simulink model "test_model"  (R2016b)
settings: Solver=VariableStepAuto  StartTime=0.0  StopTime=runtime  RelTol=1e-3
InitFcn:
  | clear mex
  | delete test_model_sfun.mexw64
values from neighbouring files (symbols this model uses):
  g = 9.81    [modelParameters.m]
  height_controlled_o = (((Rm*If +      + (((omega0_o * 2 * Rm * Kv * Kq       * Kd + 1)^2) - 1)/(4* Rm*Kv^2*Kq      *Kd))/Vb)*(Pmax- Pmin)+Pmin)    [modelParameters.m]
  If = 0.511    [modelParameters.m]
  Jreq = 4.2012e-05    [modelParameters.m]
  Jxx = 0.0130    (= 0.013)    [modelParameters.m]
  Jyy = 0.0140    (= 0.014)    [modelParameters.m]
  Jzz = 0.0285    [modelParameters.m]
  Kd = 1.0317e-7    (= 1.0317e-07)    [modelParameters.m]
  Kq = 96.3422    [modelParameters.m]
  Kt = 8.6519e-6    (= 8.6519e-06)    [modelParameters.m]
  Kv = 96.3422    [modelParameters.m]
  m = 1.244    [modelParameters.m]
  omega0_o = (-1 + sqrt(1 - 4*Rm*Kv*Kq*Kd*( Kv*Rm*If - Kv*Vb_eff_0))) / (2*Rm*Kv*Kq*Kd)    [modelParameters.m]
  omega1_o = (-1 + sqrt(1 - 4*Rm*Kv*Kq*Kd*( Kv*Rm*If - Kv*Vb_eff_1))) / (2*Rm*Kv*Kq*Kd)    [modelParameters.m]
  omega2_o = (-1 + sqrt(1 - 4*Rm*Kv*Kq*Kd*( Kv*Rm*If - Kv*Vb_eff_2))) / (2*Rm*Kv*Kq*Kd)    [modelParameters.m]
  omega3_o = (-1 + sqrt(1 - 4*Rm*Kv*Kq*Kd*( Kv*Rm*If - Kv*Vb_eff_3))) / (2*Rm*Kv*Kq*Kd)    [modelParameters.m]
  pitch_o = pitch_value(1)    [modelParameters.m]
  pitchrate_o = pitchrate_value(1)    [modelParameters.m]
  Pmax = 2e5    (= 200000)    [modelParameters.m]
  Pmin = 1e5    (= 100000)    [modelParameters.m]
  rhx = 0.16    [modelParameters.m]
  rhy = 0.16    [modelParameters.m]
  rhz = 0.03    [modelParameters.m]
  Rm = 0.2308    [modelParameters.m]
  roll_o = roll_value(1)    [modelParameters.m]
  rollrate_o = rollrate_value(1)    [modelParameters.m]
  Tc = 0.04    [modelParameters.m]
  Tq = 0.005    [modelParameters.m]
  Vb = 11.1    [modelParameters.m]
  x_controlled_o = 0    [modelParameters.m]
  x_o = x_position(1)    [modelParameters.m]
  x_vel_o = (x_position(2) - x_position(1)) / (time(2) - time(1))    [modelParameters.m]
  y_controlled_o = 0    [modelParameters.m]
  y_o = y_position(1)    [modelParameters.m]
  y_vel_o = (y_position(2) - y_position(1)) / (time(2) - time(1))    [modelParameters.m]
  yaw_controlled_o = 0    [modelParameters.m]
  yaw_o = yaw_value(1)    [modelParameters.m]
  yawrate_o = yawrate_value(1)    [modelParameters.m]
  z_o = z_position(1)    [modelParameters.m]
  z_vel_o = (z_position(2) - z_position(1)) / (time(2) - time(1))    [modelParameters.m]
undefined symbols (not defined in the file or in its folder): DiscIntNeverNeededParam
libraries: simulink x21, vrlib x2
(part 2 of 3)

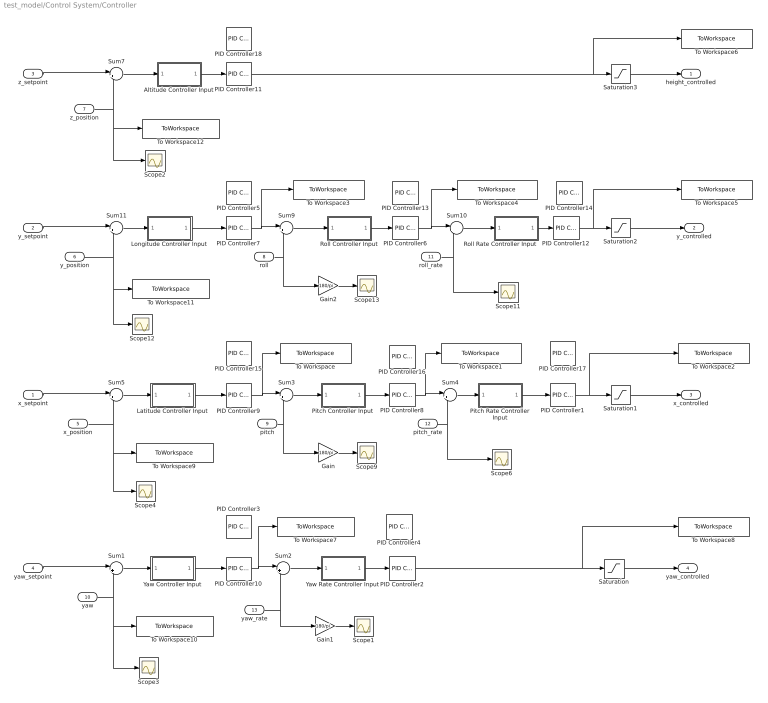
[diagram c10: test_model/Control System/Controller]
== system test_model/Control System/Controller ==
  x_setpoint : Inport
  y_setpoint : Inport  Port=2
  z_setpoint : Inport  Port=3
  yaw_setpoint : Inport  Port=4
  x_position : Inport  Port=5
  y_position : Inport  Port=6
  z_position : Inport  Port=7
  roll : Inport  Port=8
  pitch : Inport  Port=9
  yaw : Inport  Port=10
  roll_rate : Inport  Port=11
  pitch_rate : Inport  Port=12
  yaw_rate : Inport  Port=13
  Altitude Controller Input : Subsystem  Variant=on
  Gain : Gain  Gain=180/pi
  Gain1 : Gain  Gain=180/pi
  Gain2 : Gain  Gain=180/pi
  Latitude Controller Input : Subsystem  Variant=on
  Longitude Controller Input : Subsystem  Variant=on
  PID Controller1 : simulink/Continuous/PID Controller  Controller=PD  TimeDomain=Discrete-time  SampleTime=Tq  IntegratorMethod=Forward Euler  FilterMethod=Forward Euler  Form=Parallel  UseFilter=off  ControllerParametersSource=internal  P=4600  I=1575.82088970639  D=550  N=244.660686071579  InitialConditionSource=internal  InitialConditionForIntegrator=0  InitialConditionForFilter=0  ExternalReset=none  LimitOutput=off  UpperSaturationLimit=inf  LowerSaturationLimit=-inf  LinearizeAsGain=on  AntiWindupMode=none  Kb=1  TrackingMode=off  Kt=1  PParamMin=[]  PParamMax=[]  IParamMin=[]  IParamMax=[]  DParamMin=[]  DParamMax=[]  NParamMin=[]  NParamMax=[]  KbParamMin=[]  KbParamMax=[]  KtParamMin=[]  KtParamMax=[]  POutMin=[]  POutMax=[]  IOutMin=[]  IOutMax=[]  DOutMin=[]  DOutMax=[]  NOutMin=[]  NOutMax=[]  KbOutMin=[]  KbOutMax=[]  KtOutMin=[]  KtOutMax=[]  IntegratorOutMin=[]  IntegratorOutMax=[]  FilterOutMin=[]  FilterOutMax=[]  SumOutMin=[]  SumOutMax=[]  SumI1OutMin=[]  SumI1OutMax=[]  SumI2OutMin=[]  SumI2OutMax=[]  SumI3OutMin=[]  SumI3OutMax=[]  SumDOutMin=[]  SumDOutMax=[]  SaturationOutMin=[]  SaturationOutMax=[]  IntegratorContinuousStateAttributes=''  IntegratorStateMustResolveToSignalObject=off  IntegratorRTWStateStorageClass=Auto  FilterContinuousStateAttributes=''  FilterStateMustResolveToSignalObject=off  FilterRTWStateStorageClass=Auto  DifferentiatorICPrevScaledInput=0  DifferentiatorOutMin=[]  DifferentiatorOutMax=[]
  PID Controller10 : simulink/Continuous/PID Controller  Controller=PD  TimeDomain=Discrete-time  SampleTime=Tc  IntegratorMethod=Forward Euler  FilterMethod=Forward Euler  Form=Parallel  UseFilter=off  ControllerParametersSource=internal  P=2.6  I=2.36803176515497  D=0  N=3.83298618768959  InitialConditionSource=internal  InitialConditionForIntegrator=0  InitialConditionForFilter=0  ExternalReset=none  LimitOutput=off  UpperSaturationLimit=inf  LowerSaturationLimit=-inf  LinearizeAsGain=on  AntiWindupMode=none  Kb=1  TrackingMode=off  Kt=1  PParamMin=[]  PParamMax=[]  IParamMin=[]  IParamMax=[]  DParamMin=[]  DParamMax=[]  NParamMin=[]  NParamMax=[]  KbParamMin=[]  KbParamMax=[]  KtParamMin=[]  KtParamMax=[]  POutMin=[]  POutMax=[]  IOutMin=[]  IOutMax=[]  DOutMin=[]  DOutMax=[]  NOutMin=[]  NOutMax=[]  KbOutMin=[]  KbOutMax=[]  KtOutMin=[]  KtOutMax=[]  IntegratorOutMin=[]  IntegratorOutMax=[]  FilterOutMin=[]  FilterOutMax=[]  SumOutMin=[]  SumOutMax=[]  SumI1OutMin=[]  SumI1OutMax=[]  SumI2OutMin=[]  SumI2OutMax=[]  SumI3OutMin=[]  SumI3OutMax=[]  SumDOutMin=[]  SumDOutMax=[]  SaturationOutMin=[]  SaturationOutMax=[]  IntegratorContinuousStateAttributes=''  IntegratorStateMustResolveToSignalObject=off  IntegratorRTWStateStorageClass=Auto  FilterContinuousStateAttributes=''  FilterStateMustResolveToSignalObject=off  FilterRTWStateStorageClass=Auto  DifferentiatorICPrevScaledInput=0  DifferentiatorOutMin=[]  DifferentiatorOutMax=[]
  PID Controller11 : simulink/Continuous/PID Controller  Controller=PID  TimeDomain=Discrete-time  SampleTime=Tc  IntegratorMethod=Forward Euler  FilterMethod=Forward Euler  Form=Parallel  UseFilter=off  ControllerParametersSource=internal  P=9804  I=817  D=7353  N=5.79502261645411  InitialConditionSource=internal  InitialConditionForIntegrator=0  InitialConditionForFilter=0  ExternalReset=none  LimitOutput=off  UpperSaturationLimit=inf  LowerSaturationLimit=-inf  LinearizeAsGain=on  AntiWindupMode=none  Kb=1  TrackingMode=off  Kt=1  PParamMin=[]  PParamMax=[]  IParamMin=[]  IParamMax=[]  DParamMin=[]  DParamMax=[]  NParamMin=[]  NParamMax=[]  KbParamMin=[]  KbParamMax=[]  KtParamMin=[]  KtParamMax=[]  POutMin=[]  POutMax=[]  IOutMin=[]  IOutMax=[]  DOutMin=[]  DOutMax=[]  NOutMin=[]  NOutMax=[]  KbOutMin=[]  KbOutMax=[]  KtOutMin=[]  KtOutMax=[]  IntegratorOutMin=[]  IntegratorOutMax=[]  FilterOutMin=[]  FilterOutMax=[]  SumOutMin=[]  SumOutMax=[]  SumI1OutMin=[]  SumI1OutMax=[]  SumI2OutMin=[]  SumI2OutMax=[]  SumI3OutMin=[]  SumI3OutMax=[]  SumDOutMin=[]  SumDOutMax=[]  SaturationOutMin=[]  SaturationOutMax=[]  IntegratorContinuousStateAttributes=''  IntegratorStateMustResolveToSignalObject=off  IntegratorRTWStateStorageClass=Auto  FilterContinuousStateAttributes=''  FilterStateMustResolveToSignalObject=off  FilterRTWStateStorageClass=Auto  DifferentiatorICPrevScaledInput=0  DifferentiatorOutMin=[]  DifferentiatorOutMax=[]
  PID Controller12 : simulink/Continuous/PID Controller  Controller=PD  TimeDomain=Discrete-time  SampleTime=Tq  IntegratorMethod=Forward Euler  FilterMethod=Forward Euler  Form=Parallel  UseFilter=off  ControllerParametersSource=internal  P=4600  I=1575.82088970639  D=550  N=244.660686071579  InitialConditionSource=internal  InitialConditionForIntegrator=0  InitialConditionForFilter=0  ExternalReset=none  LimitOutput=off  UpperSaturationLimit=inf  LowerSaturationLimit=-inf  LinearizeAsGain=on  AntiWindupMode=none  Kb=1  TrackingMode=off  Kt=1  PParamMin=[]  PParamMax=[]  IParamMin=[]  IParamMax=[]  DParamMin=[]  DParamMax=[]  NParamMin=[]  NParamMax=[]  KbParamMin=[]  KbParamMax=[]  KtParamMin=[]  KtParamMax=[]  POutMin=[]  POutMax=[]  IOutMin=[]  IOutMax=[]  DOutMin=[]  DOutMax=[]  NOutMin=[]  NOutMax=[]  KbOutMin=[]  KbOutMax=[]  KtOutMin=[]  KtOutMax=[]  IntegratorOutMin=[]  IntegratorOutMax=[]  FilterOutMin=[]  FilterOutMax=[]  SumOutMin=[]  SumOutMax=[]  SumI1OutMin=[]  SumI1OutMax=[]  SumI2OutMin=[]  SumI2OutMax=[]  SumI3OutMin=[]  SumI3OutMax=[]  SumDOutMin=[]  SumDOutMax=[]  SaturationOutMin=[]  SaturationOutMax=[]  IntegratorContinuousStateAttributes=''  IntegratorStateMustResolveToSignalObject=off  IntegratorRTWStateStorageClass=Auto  FilterContinuousStateAttributes=''  FilterStateMustResolveToSignalObject=off  FilterRTWStateStorageClass=Auto  DifferentiatorICPrevScaledInput=0  DifferentiatorOutMin=[]  DifferentiatorOutMax=[]
  PID Controller13 : simulink/Continuous/PID Controller  Controller=P  TimeDomain=Discrete-time  SampleTime=Tc  IntegratorMethod=Forward Euler  FilterMethod=Forward Euler  Form=Parallel  UseFilter=off  ControllerParametersSource=internal  P=1  I=35.1207902652377  D=0.2  N=40.0107970227961  InitialConditionSource=internal  InitialConditionForIntegrator=0  InitialConditionForFilter=0  ExternalReset=none  LimitOutput=off  UpperSaturationLimit=inf  LowerSaturationLimit=-inf  LinearizeAsGain=on  AntiWindupMode=none  Kb=1  TrackingMode=off  Kt=1  PParamMin=[]  PParamMax=[]  IParamMin=[]  IParamMax=[]  DParamMin=[]  DParamMax=[]  NParamMin=[]  NParamMax=[]  KbParamMin=[]  KbParamMax=[]  KtParamMin=[]  KtParamMax=[]  POutMin=[]  POutMax=[]  IOutMin=[]  IOutMax=[]  DOutMin=[]  DOutMax=[]  NOutMin=[]  NOutMax=[]  KbOutMin=[]  KbOutMax=[]  KtOutMin=[]  KtOutMax=[]  IntegratorOutMin=[]  IntegratorOutMax=[]  FilterOutMin=[]  FilterOutMax=[]  SumOutMin=[]  SumOutMax=[]  SumI1OutMin=[]  SumI1OutMax=[]  SumI2OutMin=[]  SumI2OutMax=[]  SumI3OutMin=[]  SumI3OutMax=[]  SumDOutMin=[]  SumDOutMax=[]  SaturationOutMin=[]  SaturationOutMax=[]  IntegratorContinuousStateAttributes=''  IntegratorStateMustResolveToSignalObject=off  IntegratorRTWStateStorageClass=Auto  FilterContinuousStateAttributes=''  FilterStateMustResolveToSignalObject=off  FilterRTWStateStorageClass=Auto  DifferentiatorICPrevScaledInput=0  DifferentiatorOutMin=[]  DifferentiatorOutMax=[]
  PID Controller14 : simulink/Continuous/PID Controller  Controller=P  TimeDomain=Discrete-time  SampleTime=Tq  IntegratorMethod=Forward Euler  FilterMethod=Forward Euler  Form=Parallel  UseFilter=off  ControllerParametersSource=internal  P=1835.12180866282  I=1575.82088970639  D=550  N=244.660686071579  InitialConditionSource=internal  InitialConditionForIntegrator=0  InitialConditionForFilter=0  ExternalReset=none  LimitOutput=off  UpperSaturationLimit=inf  LowerSaturationLimit=-inf  LinearizeAsGain=on  AntiWindupMode=none  Kb=1  TrackingMode=off  Kt=1  PParamMin=[]  PParamMax=[]  IParamMin=[]  IParamMax=[]  DParamMin=[]  DParamMax=[]  NParamMin=[]  NParamMax=[]  KbParamMin=[]  KbParamMax=[]  KtParamMin=[]  KtParamMax=[]  POutMin=[]  POutMax=[]  IOutMin=[]  IOutMax=[]  DOutMin=[]  DOutMax=[]  NOutMin=[]  NOutMax=[]  KbOutMin=[]  KbOutMax=[]  KtOutMin=[]  KtOutMax=[]  IntegratorOutMin=[]  IntegratorOutMax=[]  FilterOutMin=[]  FilterOutMax=[]  SumOutMin=[]  SumOutMax=[]  SumI1OutMin=[]  SumI1OutMax=[]  SumI2OutMin=[]  SumI2OutMax=[]  SumI3OutMin=[]  SumI3OutMax=[]  SumDOutMin=[]  SumDOutMax=[]  SaturationOutMin=[]  SaturationOutMax=[]  IntegratorContinuousStateAttributes=''  IntegratorStateMustResolveToSignalObject=off  IntegratorRTWStateStorageClass=Auto  FilterContinuousStateAttributes=''  FilterStateMustResolveToSignalObject=off  FilterRTWStateStorageClass=Auto  DifferentiatorICPrevScaledInput=0  DifferentiatorOutMin=[]  DifferentiatorOutMax=[]
  PID Controller15 : simulink/Continuous/PID Controller  Controller=PD  TimeDomain=Discrete-time  SampleTime=Tc  IntegratorMethod=Forward Euler  FilterMethod=Forward Euler  Form=Parallel  UseFilter=on  ControllerParametersSource=internal  P=-0.00239291827793903  I=0.005  D=-0.101936697537801  N=33.9318377685715  InitialConditionSource=internal  InitialConditionForIntegrator=0  InitialConditionForFilter=0  ExternalReset=none  LimitOutput=off  UpperSaturationLimit=inf  LowerSaturationLimit=-inf  LinearizeAsGain=on  AntiWindupMode=none  Kb=1  TrackingMode=off  Kt=1  PParamMin=[]  PParamMax=[]  IParamMin=[]  IParamMax=[]  DParamMin=[]  DParamMax=[]  NParamMin=[]  NParamMax=[]  KbParamMin=[]  KbParamMax=[]  KtParamMin=[]  KtParamMax=[]  POutMin=[]  POutMax=[]  IOutMin=[]  IOutMax=[]  DOutMin=[]  DOutMax=[]  NOutMin=[]  NOutMax=[]  KbOutMin=[]  KbOutMax=[]  KtOutMin=[]  KtOutMax=[]  IntegratorOutMin=[]  IntegratorOutMax=[]  FilterOutMin=[]  FilterOutMax=[]  SumOutMin=[]  SumOutMax=[]  SumI1OutMin=[]  SumI1OutMax=[]  SumI2OutMin=[]  SumI2OutMax=[]  SumI3OutMin=[]  SumI3OutMax=[]  SumDOutMin=[]  SumDOutMax=[]  SaturationOutMin=[]  SaturationOutMax=[]  IntegratorContinuousStateAttributes=''  IntegratorStateMustResolveToSignalObject=off  IntegratorRTWStateStorageClass=Auto  FilterContinuousStateAttributes=''  FilterStateMustResolveToSignalObject=off  FilterRTWStateStorageClass=Auto  DifferentiatorICPrevScaledInput=0  DifferentiatorOutMin=[]  DifferentiatorOutMax=[]
  PID Controller16 : simulink/Continuous/PID Controller  Controller=P  TimeDomain=Discrete-time  SampleTime=Tc  IntegratorMethod=Forward Euler  FilterMethod=Forward Euler  Form=Parallel  UseFilter=off  ControllerParametersSource=internal  P=1  I=35.1207902652377  D=0.2  N=40.0107970227961  InitialConditionSource=internal  InitialConditionForIntegrator=0  InitialConditionForFilter=0  ExternalReset=none  LimitOutput=off  UpperSaturationLimit=inf  LowerSaturationLimit=-inf  LinearizeAsGain=on  AntiWindupMode=none  Kb=1  TrackingMode=off  Kt=1  PParamMin=[]  PParamMax=[]  IParamMin=[]  IParamMax=[]  DParamMin=[]  DParamMax=[]  NParamMin=[]  NParamMax=[]  KbParamMin=[]  KbParamMax=[]  KtParamMin=[]  KtParamMax=[]  POutMin=[]  POutMax=[]  IOutMin=[]  IOutMax=[]  DOutMin=[]  DOutMax=[]  NOutMin=[]  NOutMax=[]  KbOutMin=[]  KbOutMax=[]  KtOutMin=[]  KtOutMax=[]  IntegratorOutMin=[]  IntegratorOutMax=[]  FilterOutMin=[]  FilterOutMax=[]  SumOutMin=[]  SumOutMax=[]  SumI1OutMin=[]  SumI1OutMax=[]  SumI2OutMin=[]  SumI2OutMax=[]  SumI3OutMin=[]  SumI3OutMax=[]  SumDOutMin=[]  SumDOutMax=[]  SaturationOutMin=[]  SaturationOutMax=[]  IntegratorContinuousStateAttributes=''  IntegratorStateMustResolveToSignalObject=off  IntegratorRTWStateStorageClass=Auto  FilterContinuousStateAttributes=''  FilterStateMustResolveToSignalObject=off  FilterRTWStateStorageClass=Auto  DifferentiatorICPrevScaledInput=0  DifferentiatorOutMin=[]  DifferentiatorOutMax=[]
  PID Controller17 : simulink/Continuous/PID Controller  Controller=P  TimeDomain=Discrete-time  SampleTime=Tq  IntegratorMethod=Forward Euler  FilterMethod=Forward Euler  Form=Parallel  UseFilter=off  ControllerParametersSource=internal  P=1835.12180866282  I=1575.82088970639  D=550  N=244.660686071579  InitialConditionSource=internal  InitialConditionForIntegrator=0  InitialConditionForFilter=0  ExternalReset=none  LimitOutput=off  UpperSaturationLimit=inf  LowerSaturationLimit=-inf  LinearizeAsGain=on  AntiWindupMode=none  Kb=1  TrackingMode=off  Kt=1  PParamMin=[]  PParamMax=[]  IParamMin=[]  IParamMax=[]  DParamMin=[]  DParamMax=[]  NParamMin=[]  NParamMax=[]  KbParamMin=[]  KbParamMax=[]  KtParamMin=[]  KtParamMax=[]  POutMin=[]  POutMax=[]  IOutMin=[]  IOutMax=[]  DOutMin=[]  DOutMax=[]  NOutMin=[]  NOutMax=[]  KbOutMin=[]  KbOutMax=[]  KtOutMin=[]  KtOutMax=[]  IntegratorOutMin=[]  IntegratorOutMax=[]  FilterOutMin=[]  FilterOutMax=[]  SumOutMin=[]  SumOutMax=[]  SumI1OutMin=[]  SumI1OutMax=[]  SumI2OutMin=[]  SumI2OutMax=[]  SumI3OutMin=[]  SumI3OutMax=[]  SumDOutMin=[]  SumDOutMax=[]  SaturationOutMin=[]  SaturationOutMax=[]  IntegratorContinuousStateAttributes=''  IntegratorStateMustResolveToSignalObject=off  IntegratorRTWStateStorageClass=Auto  FilterContinuousStateAttributes=''  FilterStateMustResolveToSignalObject=off  FilterRTWStateStorageClass=Auto  DifferentiatorICPrevScaledInput=0  DifferentiatorOutMin=[]  DifferentiatorOutMax=[]
  PID Controller18 : simulink/Continuous/PID Controller  Controller=PID  TimeDomain=Discrete-time  SampleTime=Tc  IntegratorMethod=Forward Euler  FilterMethod=Forward Euler  Form=Parallel  UseFilter=off  ControllerParametersSource=internal  P=-3138.91816077077  I=-320.189162634817  D=-7421.98260028101  N=5.79502261645411  InitialConditionSource=internal  InitialConditionForIntegrator=0  InitialConditionForFilter=0  ExternalReset=none  LimitOutput=off  UpperSaturationLimit=inf  LowerSaturationLimit=-inf  LinearizeAsGain=on  AntiWindupMode=none  Kb=1  TrackingMode=off  Kt=1  PParamMin=[]  PParamMax=[]  IParamMin=[]  IParamMax=[]  DParamMin=[]  DParamMax=[]  NParamMin=[]  NParamMax=[]  KbParamMin=[]  KbParamMax=[]  KtParamMin=[]  KtParamMax=[]  POutMin=[]  POutMax=[]  IOutMin=[]  IOutMax=[]  DOutMin=[]  DOutMax=[]  NOutMin=[]  NOutMax=[]  KbOutMin=[]  KbOutMax=[]  KtOutMin=[]  KtOutMax=[]  IntegratorOutMin=[]  IntegratorOutMax=[]  FilterOutMin=[]  FilterOutMax=[]  SumOutMin=[]  SumOutMax=[]  SumI1OutMin=[]  SumI1OutMax=[]  SumI2OutMin=[]  SumI2OutMax=[]  SumI3OutMin=[]  SumI3OutMax=[]  SumDOutMin=[]  SumDOutMax=[]  SaturationOutMin=[]  SaturationOutMax=[]  IntegratorContinuousStateAttributes=''  IntegratorStateMustResolveToSignalObject=off  IntegratorRTWStateStorageClass=Auto  FilterContinuousStateAttributes=''  FilterStateMustResolveToSignalObject=off  FilterRTWStateStorageClass=Auto  DifferentiatorICPrevScaledInput=0  DifferentiatorOutMin=[]  DifferentiatorOutMax=[]
  PID Controller2 : simulink/Continuous/PID Controller  Controller=P  TimeDomain=Discrete-time  SampleTime=Tq  IntegratorMethod=Forward Euler  FilterMethod=Forward Euler  Form=Parallel  UseFilter=on  ControllerParametersSource=internal  P=435480  I=-77.7  D=2.32  N=1/0.0818  InitialConditionSource=internal  InitialConditionForIntegrator=0  InitialConditionForFilter=0  ExternalReset=none  ZeroCross=off  LimitOutput=off  UpperSaturationLimit=inf  LowerSaturationLimit=-inf  LinearizeAsGain=on  AntiWindupMode=none  Kb=1  TrackingMode=off  Kt=1  PParamMin=[]  PParamMax=[]  IParamMin=[]  IParamMax=[]  DParamMin=[]  DParamMax=[]  NParamMin=[]  NParamMax=[]  KbParamMin=[]  KbParamMax=[]  KtParamMin=[]  KtParamMax=[]  POutMin=[]  POutMax=[]  IOutMin=[]  IOutMax=[]  DOutMin=[]  DOutMax=[]  NOutMin=[]  NOutMax=[]  KbOutMin=[]  KbOutMax=[]  KtOutMin=[]  KtOutMax=[]  IntegratorOutMin=[]  IntegratorOutMax=[]  FilterOutMin=[]  FilterOutMax=[]  SumOutMin=[]  SumOutMax=[]  SumI1OutMin=[]  SumI1OutMax=[]  SumI2OutMin=[]  SumI2OutMax=[]  SumI3OutMin=[]  SumI3OutMax=[]  SumDOutMin=[]  SumDOutMax=[]  SaturationOutMin=[]  SaturationOutMax=[]  IntegratorContinuousStateAttributes=''  IntegratorStateMustResolveToSignalObject=off  IntegratorRTWStateStorageClass=Auto  FilterContinuousStateAttributes=''  FilterStateMustResolveToSignalObject=off  FilterRTWStateStorageClass=Auto  DifferentiatorICPrevScaledInput=0  DifferentiatorOutMin=[]  DifferentiatorOutMax=[]
  PID Controller3 : simulink/Continuous/PID Controller  Controller=PD  TimeDomain=Discrete-time  SampleTime=Tc  IntegratorMethod=Forward Euler  FilterMethod=Forward Euler  Form=Parallel  UseFilter=on  ControllerParametersSource=internal  P=4.73868196952772  I=2.36803176515497  D=1.0129554639517  N=3.83298618768959  InitialConditionSource=internal  InitialConditionForIntegrator=0  InitialConditionForFilter=0  ExternalReset=none  LimitOutput=off  UpperSaturationLimit=inf  LowerSaturationLimit=-inf  LinearizeAsGain=on  AntiWindupMode=none  Kb=1  TrackingMode=off  Kt=1  PParamMin=[]  PParamMax=[]  IParamMin=[]  IParamMax=[]  DParamMin=[]  DParamMax=[]  NParamMin=[]  NParamMax=[]  KbParamMin=[]  KbParamMax=[]  KtParamMin=[]  KtParamMax=[]  POutMin=[]  POutMax=[]  IOutMin=[]  IOutMax=[]  DOutMin=[]  DOutMax=[]  NOutMin=[]  NOutMax=[]  KbOutMin=[]  KbOutMax=[]  KtOutMin=[]  KtOutMax=[]  IntegratorOutMin=[]  IntegratorOutMax=[]  FilterOutMin=[]  FilterOutMax=[]  SumOutMin=[]  SumOutMax=[]  SumI1OutMin=[]  SumI1OutMax=[]  SumI2OutMin=[]  SumI2OutMax=[]  SumI3OutMin=[]  SumI3OutMax=[]  SumDOutMin=[]  SumDOutMax=[]  SaturationOutMin=[]  SaturationOutMax=[]  IntegratorContinuousStateAttributes=''  IntegratorStateMustResolveToSignalObject=off  IntegratorRTWStateStorageClass=Auto  FilterContinuousStateAttributes=''  FilterStateMustResolveToSignalObject=off  FilterRTWStateStorageClass=Auto  DifferentiatorICPrevScaledInput=0  DifferentiatorOutMin=[]  DifferentiatorOutMax=[]
  PID Controller4 : simulink/Continuous/PID Controller  Controller=P  TimeDomain=Discrete-time  SampleTime=Tc  IntegratorMethod=Forward Euler  FilterMethod=Forward Euler  Form=Parallel  UseFilter=on  ControllerParametersSource=internal  P=10205.7985086303  I=-77.7  D=2.32  N=1/0.0818  InitialConditionSource=internal  InitialConditionForIntegrator=0  InitialConditionForFilter=0  ExternalReset=none  ZeroCross=off  LimitOutput=off  UpperSaturationLimit=inf  LowerSaturationLimit=-inf  LinearizeAsGain=on  AntiWindupMode=none  Kb=1  TrackingMode=off  Kt=1  PParamMin=[]  PParamMax=[]  IParamMin=[]  IParamMax=[]  DParamMin=[]  DParamMax=[]  NParamMin=[]  NParamMax=[]  KbParamMin=[]  KbParamMax=[]  KtParamMin=[]  KtParamMax=[]  POutMin=[]  POutMax=[]  IOutMin=[]  IOutMax=[]  DOutMin=[]  DOutMax=[]  NOutMin=[]  NOutMax=[]  KbOutMin=[]  KbOutMax=[]  KtOutMin=[]  KtOutMax=[]  IntegratorOutMin=[]  IntegratorOutMax=[]  FilterOutMin=[]  FilterOutMax=[]  SumOutMin=[]  SumOutMax=[]  SumI1OutMin=[]  SumI1OutMax=[]  SumI2OutMin=[]  SumI2OutMax=[]  SumI3OutMin=[]  SumI3OutMax=[]  SumDOutMin=[]  SumDOutMax=[]  SaturationOutMin=[]  SaturationOutMax=[]  IntegratorContinuousStateAttributes=''  IntegratorStateMustResolveToSignalObject=off  IntegratorRTWStateStorageClass=Auto  FilterContinuousStateAttributes=''  FilterStateMustResolveToSignalObject=off  FilterRTWStateStorageClass=Auto  DifferentiatorICPrevScaledInput=0  DifferentiatorOutMin=[]  DifferentiatorOutMax=[]
  PID Controller5 : simulink/Continuous/PID Controller  Controller=PD  TimeDomain=Discrete-time  SampleTime=Tc  IntegratorMethod=Forward Euler  FilterMethod=Forward Euler  Form=Parallel  UseFilter=on  ControllerParametersSource=internal  P=-0.00239291827793903  I=0.005  D=-0.101936697537801  N=33.9318377685715  InitialConditionSource=internal  InitialConditionForIntegrator=0  InitialConditionForFilter=0  ExternalReset=none  LimitOutput=off  UpperSaturationLimit=inf  LowerSaturationLimit=-inf  LinearizeAsGain=on  AntiWindupMode=none  Kb=1  TrackingMode=off  Kt=1  PParamMin=[]  PParamMax=[]  IParamMin=[]  IParamMax=[]  DParamMin=[]  DParamMax=[]  NParamMin=[]  NParamMax=[]  KbParamMin=[]  KbParamMax=[]  KtParamMin=[]  KtParamMax=[]  POutMin=[]  POutMax=[]  IOutMin=[]  IOutMax=[]  DOutMin=[]  DOutMax=[]  NOutMin=[]  NOutMax=[]  KbOutMin=[]  KbOutMax=[]  KtOutMin=[]  KtOutMax=[]  IntegratorOutMin=[]  IntegratorOutMax=[]  FilterOutMin=[]  FilterOutMax=[]  SumOutMin=[]  SumOutMax=[]  SumI1OutMin=[]  SumI1OutMax=[]  SumI2OutMin=[]  SumI2OutMax=[]  SumI3OutMin=[]  SumI3OutMax=[]  SumDOutMin=[]  SumDOutMax=[]  SaturationOutMin=[]  SaturationOutMax=[]  IntegratorContinuousStateAttributes=''  IntegratorStateMustResolveToSignalObject=off  IntegratorRTWStateStorageClass=Auto  FilterContinuousStateAttributes=''  FilterStateMustResolveToSignalObject=off  FilterRTWStateStorageClass=Auto  DifferentiatorICPrevScaledInput=0  DifferentiatorOutMin=[]  DifferentiatorOutMax=[]
  PID Controller6 : simulink/Continuous/PID Controller  Controller=PD  TimeDomain=Discrete-time  SampleTime=Tq  IntegratorMethod=Forward Euler  FilterMethod=Forward Euler  Form=Parallel  UseFilter=off  ControllerParametersSource=internal  P=15  I=35.1207902652377  D=0.2  N=40.0107970227961  InitialConditionSource=internal  InitialConditionForIntegrator=0  InitialConditionForFilter=0  ExternalReset=none  LimitOutput=off  UpperSaturationLimit=inf  LowerSaturationLimit=-inf  LinearizeAsGain=on  AntiWindupMode=none  Kb=1  TrackingMode=off  Kt=1  PParamMin=[]  PParamMax=[]  IParamMin=[]  IParamMax=[]  DParamMin=[]  DParamMax=[]  NParamMin=[]  NParamMax=[]  KbParamMin=[]  KbParamMax=[]  KtParamMin=[]  KtParamMax=[]  POutMin=[]  POutMax=[]  IOutMin=[]  IOutMax=[]  DOutMin=[]  DOutMax=[]  NOutMin=[]  NOutMax=[]  KbOutMin=[]  KbOutMax=[]  KtOutMin=[]  KtOutMax=[]  IntegratorOutMin=[]  IntegratorOutMax=[]  FilterOutMin=[]  FilterOutMax=[]  SumOutMin=[]  SumOutMax=[]  SumI1OutMin=[]  SumI1OutMax=[]  SumI2OutMin=[]  SumI2OutMax=[]  SumI3OutMin=[]  SumI3OutMax=[]  SumDOutMin=[]  SumDOutMax=[]  SaturationOutMin=[]  SaturationOutMax=[]  IntegratorContinuousStateAttributes=''  IntegratorStateMustResolveToSignalObject=off  IntegratorRTWStateStorageClass=Auto  FilterContinuousStateAttributes=''  FilterStateMustResolveToSignalObject=off  FilterRTWStateStorageClass=Auto  DifferentiatorICPrevScaledInput=0  DifferentiatorOutMin=[]  DifferentiatorOutMax=[]
  PID Controller7 : simulink/Continuous/PID Controller  Controller=PID  TimeDomain=Discrete-time  SampleTime=Tc  IntegratorMethod=Forward Euler  FilterMethod=Forward Euler  Form=Parallel  UseFilter=off  ControllerParametersSource=internal  P=0.015  I=0.005  D=0.03  N=33.9318377685715  InitialConditionSource=internal  InitialConditionForIntegrator=0  InitialConditionForFilter=0  ExternalReset=none  LimitOutput=off  UpperSaturationLimit=inf  LowerSaturationLimit=-inf  LinearizeAsGain=on  AntiWindupMode=none  Kb=1  TrackingMode=off  Kt=1  PParamMin=[]  PParamMax=[]  IParamMin=[]  IParamMax=[]  DParamMin=[]  DParamMax=[]  NParamMin=[]  NParamMax=[]  KbParamMin=[]  KbParamMax=[]  KtParamMin=[]  KtParamMax=[]  POutMin=[]  POutMax=[]  IOutMin=[]  IOutMax=[]  DOutMin=[]  DOutMax=[]  NOutMin=[]  NOutMax=[]  KbOutMin=[]  KbOutMax=[]  KtOutMin=[]  KtOutMax=[]  IntegratorOutMin=[]  IntegratorOutMax=[]  FilterOutMin=[]  FilterOutMax=[]  SumOutMin=[]  SumOutMax=[]  SumI1OutMin=[]  SumI1OutMax=[]  SumI2OutMin=[]  SumI2OutMax=[]  SumI3OutMin=[]  SumI3OutMax=[]  SumDOutMin=[]  SumDOutMax=[]  SaturationOutMin=[]  SaturationOutMax=[]  IntegratorContinuousStateAttributes=''  IntegratorStateMustResolveToSignalObject=off  IntegratorRTWStateStorageClass=Auto  FilterContinuousStateAttributes=''  FilterStateMustResolveToSignalObject=off  FilterRTWStateStorageClass=Auto  DifferentiatorICPrevScaledInput=0  DifferentiatorOutMin=[]  DifferentiatorOutMax=[]
  PID Controller8 : simulink/Continuous/PID Controller  Controller=PD  TimeDomain=Discrete-time  SampleTime=Tq  IntegratorMethod=Forward Euler  FilterMethod=Forward Euler  Form=Parallel  UseFilter=off  ControllerParametersSource=internal  P=15  I=35.1207902652377  D=0.2  N=40.0107970227961  InitialConditionSource=internal  InitialConditionForIntegrator=0  InitialConditionForFilter=0  ExternalReset=none  LimitOutput=off  UpperSaturationLimit=inf  LowerSaturationLimit=-inf  LinearizeAsGain=on  AntiWindupMode=none  Kb=1  TrackingMode=off  Kt=1  PParamMin=[]  PParamMax=[]  IParamMin=[]  IParamMax=[]  DParamMin=[]  DParamMax=[]  NParamMin=[]  NParamMax=[]  KbParamMin=[]  KbParamMax=[]  KtParamMin=[]  KtParamMax=[]  POutMin=[]  POutMax=[]  IOutMin=[]  IOutMax=[]  DOutMin=[]  DOutMax=[]  NOutMin=[]  NOutMax=[]  KbOutMin=[]  KbOutMax=[]  KtOutMin=[]  KtOutMax=[]  IntegratorOutMin=[]  IntegratorOutMax=[]  FilterOutMin=[]  FilterOutMax=[]  SumOutMin=[]  SumOutMax=[]  SumI1OutMin=[]  SumI1OutMax=[]  SumI2OutMin=[]  SumI2OutMax=[]  SumI3OutMin=[]  SumI3OutMax=[]  SumDOutMin=[]  SumDOutMax=[]  SaturationOutMin=[]  SaturationOutMax=[]  IntegratorContinuousStateAttributes=''  IntegratorStateMustResolveToSignalObject=off  IntegratorRTWStateStorageClass=Auto  FilterContinuousStateAttributes=''  FilterStateMustResolveToSignalObject=off  FilterRTWStateStorageClass=Auto  DifferentiatorICPrevScaledInput=0  DifferentiatorOutMin=[]  DifferentiatorOutMax=[]
  PID Controller9 : simulink/Continuous/PID Controller  Controller=PID  TimeDomain=Discrete-time  SampleTime=Tc  IntegratorMethod=Forward Euler  FilterMethod=Forward Euler  Form=Parallel  UseFilter=off  ControllerParametersSource=internal  P=-0.015  I=-0.005  D=-0.03  N=33.9318377685715  InitialConditionSource=internal  InitialConditionForIntegrator=0  InitialConditionForFilter=0  ExternalReset=none  LimitOutput=off  UpperSaturationLimit=inf  LowerSaturationLimit=-inf  LinearizeAsGain=on  AntiWindupMode=none  Kb=1  TrackingMode=off  Kt=1  PParamMin=[]  PParamMax=[]  IParamMin=[]  IParamMax=[]  DParamMin=[]  DParamMax=[]  NParamMin=[]  NParamMax=[]  KbParamMin=[]  KbParamMax=[]  KtParamMin=[]  KtParamMax=[]  POutMin=[]  POutMax=[]  IOutMin=[]  IOutMax=[]  DOutMin=[]  DOutMax=[]  NOutMin=[]  NOutMax=[]  KbOutMin=[]  KbOutMax=[]  KtOutMin=[]  KtOutMax=[]  IntegratorOutMin=[]  IntegratorOutMax=[]  FilterOutMin=[]  FilterOutMax=[]  SumOutMin=[]  SumOutMax=[]  SumI1OutMin=[]  SumI1OutMax=[]  SumI2OutMin=[]  SumI2OutMax=[]  SumI3OutMin=[]  SumI3OutMax=[]  SumDOutMin=[]  SumDOutMax=[]  SaturationOutMin=[]  SaturationOutMax=[]  IntegratorContinuousStateAttributes=''  IntegratorStateMustResolveToSignalObject=off  IntegratorRTWStateStorageClass=Auto  FilterContinuousStateAttributes=''  FilterStateMustResolveToSignalObject=off  FilterRTWStateStorageClass=Auto  DifferentiatorICPrevScaledInput=0  DifferentiatorOutMin=[]  DifferentiatorOutMax=[]
  Pitch Controller Input : Subsystem  Variant=on
  Pitch Rate Controller Input : Subsystem  Variant=on
  Roll Controller Input : Subsystem  Variant=on
  Roll Rate Controller Input : Subsystem  Variant=on
  Saturation{,1..3} (4 alike) : Saturate  UpperLimit=30000  LowerLimit=-30000
  Scope{1..4,6,9,11..13} (9 alike) : Scope
  Sum{1..5,7,9..11} (9 alike) : Sum  Inputs=|+-
  To Workspace : ToWorkspace  VariableName=pitch_setpoint_model  SaveFormat=Structure With Time  SampleTime=-1
  To Workspace1 : ToWorkspace  VariableName=pitchrate_setpoint_model  SaveFormat=Structure With Time  SampleTime=Tq
  To Workspace10 : ToWorkspace  VariableName=yaw_value_model  SaveFormat=Structure With Time  SampleTime=Tc
  To Workspace11 : ToWorkspace  VariableName=y_position_model  SaveFormat=Structure With Time  SampleTime=Tc
  To Workspace12 : ToWorkspace  VariableName=z_position_model  SaveFormat=Structure With Time  SampleTime=Tc
  To Workspace2 : ToWorkspace  VariableName=x_command_model  SaveFormat=Structure With Time  SampleTime=Tq
  To Workspace3 : ToWorkspace  VariableName=roll_setpoint_model  SaveFormat=Structure With Time  SampleTime=Tc
  To Workspace4 : ToWorkspace  VariableName=rollrate_setpoint_model  SaveFormat=Structure With Time  SampleTime=Tq
  To Workspace5 : ToWorkspace  VariableName=y_command_model  SaveFormat=Structure With Time  SampleTime=Tq
  To Workspace6 : ToWorkspace  VariableName=z_command_model  SaveFormat=Structure With Time  SampleTime=Tc
  To Workspace7 : ToWorkspace  VariableName=yawrate_setpoint_model  SaveFormat=Structure With Time  SampleTime=Tc
  To Workspace8 : ToWorkspace  VariableName=yaw_command_model  SaveFormat=Structure With Time  SampleTime=Tq
  To Workspace9 : ToWorkspace  VariableName=x_position_model  SaveFormat=Structure With Time  SampleTime=Tc
  Yaw Controller Input : Subsystem  Variant=on
  Yaw Rate Controller Input : Subsystem  Variant=on
  height_controlled : Outport
  y_controlled : Outport  Port=2
  x_controlled : Outport  Port=3
  yaw_controlled : Outport  Port=4
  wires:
  pitch_rate/1 -> Scope6/1, Sum4/2
  z_setpoint/1 -> Sum7/1
  x_position/1 -> Scope4/1, To Workspace9/1, Sum5/2
  PID Controller8/1 -> Sum4/1, To Workspace1/1
  PID Controller9/1 -> Sum3/1, To Workspace/1
  pitch/1 -> Gain/1, Sum3/2
  Gain/1 -> Scope9/1
  PID Controller2/1 -> To Workspace8/1, Saturation/1
  PID Controller1/1 -> To Workspace2/1, Saturation1/1
  Latitude Controller Input/1(x_error) -> PID Controller9/1
  x_setpoint/1 -> Sum5/1
  roll_rate/1 -> Scope11/1, Sum10/2
  y_position/1 -> Scope12/1, To Workspace11/1, Sum11/2
  PID Controller6/1 -> Sum10/1, To Workspace4/1
  PID Controller7/1 -> Sum9/1, To Workspace3/1
  roll/1 -> Gain2/1, Sum9/2
  Gain2/1 -> Scope13/1
  PID Controller12/1 -> To Workspace5/1, Saturation2/1
  y_setpoint/1 -> Sum11/1
  PID Controller11/1 -> To Workspace6/1, Saturation3/1
  Saturation1/1 -> x_controlled/1
  Saturation2/1 -> y_controlled/1
  Saturation3/1 -> height_controlled/1
  Saturation/1 -> yaw_controlled/1
  yaw/1 -> Scope3/1, To Workspace10/1, Sum1/2
  yaw_setpoint/1 -> Sum1/1
  yaw_rate/1 -> Gain1/1, Sum2/2
  Gain1/1 -> Scope1/1
  PID Controller10/1 -> To Workspace7/1, Sum2/1
  z_position/1 -> To Workspace12/1, Scope2/1, Sum7/2
  Sum1/1 -> Yaw Controller Input/1(yaw_error_model)
  Yaw Controller Input/1(yaw_error) -> PID Controller10/1
  Sum2/1 -> Yaw Rate Controller Input/1(yawrate_error_model)
  Yaw Rate Controller Input/1(yawrate_error) -> PID Controller2/1
  Sum5/1 -> Latitude Controller Input/1(x_error_model)
  Sum3/1 -> Pitch Controller Input/1(pitch_error_model)
  Pitch Controller Input/1(pitch_error) -> PID Controller8/1
  Sum4/1 -> Pitch Rate Controller Input/1(pitchrate_error_model)
  Pitch Rate Controller Input/1(pitchrate_error) -> PID Controller1/1
  Sum11/1 -> Longitude Controller Input/1(y_error_model)
  Longitude Controller Input/1(y_error) -> PID Controller7/1
  Sum9/1 -> Roll Controller Input/1(roll_error_model)
  Roll Controller Input/1(roll_error) -> PID Controller6/1
  Sum10/1 -> Roll Rate Controller Input/1(rollrate_error_model)
  Roll Rate Controller Input/1(rollrate_error) -> PID Controller12/1
  Altitude Controller Input/1(z_error) -> PID Controller11/1
  Sum7/1 -> Altitude Controller Input/1(z_error_model)

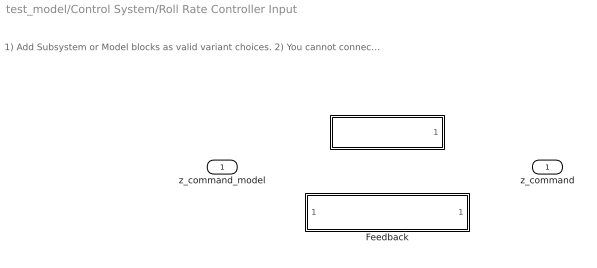
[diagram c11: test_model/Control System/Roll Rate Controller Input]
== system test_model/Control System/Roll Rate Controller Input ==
  note: 1) Add Subsystem or Model blocks as valid variant choices. 2) You cannot connect blocks at this level. At simulation, connectivity is automatically determined, based on the active variant and port name matching.
  z_command_model : Inport
  " " : Subsystem  VariantControl=logAnalysisToggle==1
  Feedback : Subsystem  VariantControl=logAnalysisToggle==0
  z_command : Outport

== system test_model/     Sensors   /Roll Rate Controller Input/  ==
  From Workspace5 : FromWorkspace  VariableName=raw_accel_data  SampleTime=Tq
  raw_accel : Outport
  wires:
  From Workspace5/1 -> raw_accel/1

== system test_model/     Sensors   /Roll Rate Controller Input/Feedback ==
  raw_accel_model : Inport
  raw_accel : Outport
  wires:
  raw_accel_model/1 -> raw_accel/1

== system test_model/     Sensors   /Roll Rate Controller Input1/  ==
  From Workspace5 : FromWorkspace  VariableName=raw_accel_data  SampleTime=Tq
  raw_gyro : Outport
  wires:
  From Workspace5/1 -> raw_gyro/1

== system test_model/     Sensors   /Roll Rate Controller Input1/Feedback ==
  raw_gyro_model : Inport
  raw_gyro : Outport
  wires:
  raw_gyro_model/1 -> raw_gyro/1

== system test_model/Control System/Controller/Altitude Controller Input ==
  note: 1) Add Subsystem or Model blocks as valid variant choices. 2) You cannot connect blocks at this level. At simulation, connectivity is automatically determined, based on the active variant and port name matching.
  z_error_model : Inport
  Feedback : Subsystem  VariantControl=logAnalysisToggle==0
  z error : Subsystem  VariantControl=logAnalysisToggle==1
  z_error : Outport

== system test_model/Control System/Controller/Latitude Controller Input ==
  note: 1) Add Subsystem or Model blocks as valid variant choices. 2) You cannot connect blocks at this level. At simulation, connectivity is automatically determined, based on the active variant and port name matching.
  x_error_model : Inport
  Feedback : Subsystem  VariantControl=logAnalysisToggle==0
  x error : Subsystem  VariantControl=logAnalysisToggle==1
  x_error : Outport

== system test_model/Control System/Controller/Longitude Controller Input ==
  note: 1) Add Subsystem or Model blocks as valid variant choices. 2) You cannot connect blocks at this level. At simulation, connectivity is automatically determined, based on the active variant and port name matching.
  y_error_model : Inport
  Feedback : Subsystem  VariantControl=logAnalysisToggle==0
  y error : Subsystem  VariantControl=logAnalysisToggle==1
  y_error : Outport

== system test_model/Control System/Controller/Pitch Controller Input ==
  note: 1) Add Subsystem or Model blocks as valid variant choices. 2) You cannot connect blocks at this level. At simulation, connectivity is automatically determined, based on the active variant and port name matching.
  pitch_error_model : Inport
  Feedback : Subsystem  VariantControl=logAnalysisToggle==0
  pitch error : Subsystem  VariantControl=logAnalysisToggle==1
  pitch_error : Outport

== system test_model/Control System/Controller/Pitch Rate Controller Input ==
  note: 1) Add Subsystem or Model blocks as valid variant choices. 2) You cannot connect blocks at this level. At simulation, connectivity is automatically determined, based on the active variant and port name matching.
  pitchrate_error_model : Inport
  Feedback : Subsystem  VariantControl=logAnalysisToggle==0
  pitchrate error : Subsystem  VariantControl=logAnalysisToggle==1
  pitchrate_error : Outport

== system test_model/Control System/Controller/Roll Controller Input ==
  note: 1) Add Subsystem or Model blocks as valid variant choices. 2) You cannot connect blocks at this level. At simulation, connectivity is automatically determined, based on the active variant and port name matching.
  roll_error_model : Inport
  Feedback : Subsystem  VariantControl=logAnalysisToggle==0
  roll error : Subsystem  VariantControl=logAnalysisToggle==1
  roll_error : Outport

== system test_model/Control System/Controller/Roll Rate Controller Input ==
  note: 1) Add Subsystem or Model blocks as valid variant choices. 2) You cannot connect blocks at this level. At simulation, connectivity is automatically determined, based on the active variant and port name matching.
  rollrate_error_model : Inport
  Feedback : Subsystem  VariantControl=logAnalysisToggle==0
  rollrate error : Subsystem  VariantControl=logAnalysisToggle==1
  rollrate_error : Outport

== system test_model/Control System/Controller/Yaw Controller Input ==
  note: 1) Add Subsystem or Model blocks as valid variant choices. 2) You cannot connect blocks at this level. At simulation, connectivity is automatically determined, based on the active variant and port name matching.
  yaw_error_model : Inport
  Feedback : Subsystem  VariantControl=logAnalysisToggle==0
  yaw error : Subsystem  VariantControl=logAnalysisToggle==1
  yaw_error : Outport

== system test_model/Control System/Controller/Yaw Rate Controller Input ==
  note: 1) Add Subsystem or Model blocks as valid variant choices. 2) You cannot connect blocks at this level. At simulation, connectivity is automatically determined, based on the active variant and port name matching.
  yawrate_error_model : Inport
  Feedback : Subsystem  VariantControl=logAnalysisToggle==0
  yawrate error : Subsystem  VariantControl=logAnalysisToggle==1
  yawrate_error : Outport

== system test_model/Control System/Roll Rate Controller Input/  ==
  From Workspace5 : FromWorkspace  VariableName=throttle_command  SampleTime=Tq
  z_command : Outport
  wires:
  From Workspace5/1 -> z_command/1

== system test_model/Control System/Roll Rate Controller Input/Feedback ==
  z_command_model : Inport
  z_command : Outport
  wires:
  z_command_model/1 -> z_command/1

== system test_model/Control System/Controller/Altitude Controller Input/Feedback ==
  z_error_model : Inport
  z_error : Outport
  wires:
  z_error_model/1 -> z_error/1

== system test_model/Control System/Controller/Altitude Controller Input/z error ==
  From Workspace6 : FromWorkspace  VariableName=z_error  SampleTime=Tc
  z_error : Outport
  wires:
  From Workspace6/1 -> z_error/1

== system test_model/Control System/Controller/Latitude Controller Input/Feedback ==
  x_error_model : Inport
  x_error : Outport
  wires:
  x_error_model/1 -> x_error/1

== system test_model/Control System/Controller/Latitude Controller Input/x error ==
  From Workspace : FromWorkspace  VariableName=x_error  SampleTime=Tc
  x_error : Outport
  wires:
  From Workspace/1 -> x_error/1

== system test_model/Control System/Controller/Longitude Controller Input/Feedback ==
  y_error_model : Inport
  y_error : Outport
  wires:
  y_error_model/1 -> y_error/1

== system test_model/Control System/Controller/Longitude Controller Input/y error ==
  From Workspace3 : FromWorkspace  VariableName=y_error  SampleTime=Tc
  y_error : Outport
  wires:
  From Workspace3/1 -> y_error/1

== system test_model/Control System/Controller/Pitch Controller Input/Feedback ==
  pitch_error_model : Inport
  pitch_error : Outport
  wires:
  pitch_error_model/1 -> pitch_error/1

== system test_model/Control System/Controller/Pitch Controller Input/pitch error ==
  From Workspace : FromWorkspace  VariableName=pitch_error  SampleTime=Tq
  pitch_error : Outport
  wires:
  From Workspace/1 -> pitch_error/1

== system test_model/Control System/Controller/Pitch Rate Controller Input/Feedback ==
  pitchrate_error_model : Inport
  pitchrate_error : Outport
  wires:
  pitchrate_error_model/1 -> pitchrate_error/1

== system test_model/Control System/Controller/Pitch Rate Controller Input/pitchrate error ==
  From Workspace2 : FromWorkspace  VariableName=pitchrate_error  SampleTime=Tq
  pitchrate_error : Outport
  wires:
  From Workspace2/1 -> pitchrate_error/1

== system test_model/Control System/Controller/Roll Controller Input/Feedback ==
  roll_error_model : Inport
  roll_error : Outport
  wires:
  roll_error_model/1 -> roll_error/1

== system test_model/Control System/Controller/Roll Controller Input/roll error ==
  From Workspace4 : FromWorkspace  VariableName=roll_error  SampleTime=Tq
  roll_error : Outport
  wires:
  From Workspace4/1 -> roll_error/1

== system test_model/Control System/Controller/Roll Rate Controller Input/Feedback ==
  rollrate_error_model : Inport
  rollrate_error : Outport
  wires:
  rollrate_error_model/1 -> rollrate_error/1

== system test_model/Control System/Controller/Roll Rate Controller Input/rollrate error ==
  From Workspace5 : FromWorkspace  VariableName=rollrate_error  SampleTime=Tq
  rollrate_error : Outport
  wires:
  From Workspace5/1 -> rollrate_error/1

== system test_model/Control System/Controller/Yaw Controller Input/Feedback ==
  yaw_error_model : Inport
  yaw_error : Outport
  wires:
  yaw_error_model/1 -> yaw_error/1

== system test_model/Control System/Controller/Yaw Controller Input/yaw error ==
  From Workspace7 : FromWorkspace  VariableName=yaw_error  SampleTime=Tc
  yaw_error : Outport
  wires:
  From Workspace7/1 -> yaw_error/1

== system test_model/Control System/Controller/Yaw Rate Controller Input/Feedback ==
  yawrate_error_model : Inport
  yawrate_error : Outport
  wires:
  yawrate_error_model/1 -> yawrate_error/1

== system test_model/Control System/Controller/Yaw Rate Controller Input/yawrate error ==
  From Workspace8 : FromWorkspace  VariableName=yawrate_error  SampleTime=Tq
  yawrate_error : Outport
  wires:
  From Workspace8/1 -> yawrate_error/1

== matlab function test_model/Actuation/Gravity

 ==
function E_Fg = gravity(m, g)

E_Fg = [0; 0; m*g];

== matlab function test_model/Actuation/Lbe





 ==
function E_ro  = linear_body_earth_conversion(B_vo, euler_angles)

euler_rates = zeros(3,1);
E_ro = zeros(3,1);

phi = euler_angles(1);
theta = euler_angles(2);
psi = euler_angles(3);

Leb = [cos(theta)*cos(psi), sin(phi)*sin(theta)*cos(psi)-cos(phi)*sin(psi), cos(phi)*sin(theta)*cos(psi)+sin(phi)*sin(psi); ...
       cos(theta)*sin(psi), sin(phi)*sin(theta)*sin(psi)+cos(phi)*cos(psi), cos(phi)*sin(theta)*sin(psi)-sin(phi)*cos(psi); ...
           -sin(theta)    ,                sin(phi)*cos(theta)            ,                 cos(phi)*cos(theta)           ];

E_ro = Leb * B_vo;

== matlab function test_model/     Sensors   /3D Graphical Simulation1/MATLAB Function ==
function y = eigenaxis_ucart(u)


if abs(u(1))< 0.0001
    u(1) = 0.0001;
end

if abs(u(2))< 0.0001
    u(2) = 0.0001;
end

if abs(u(3))< 0.0001
    u(3) = 0.0001;
end

u = [ -u(1); -u(2); u(3) ];% [Pitch, Yaw, Roll] 

C11 = cos(u(2))*cos(u(3));
C12 = cos(u(2))*sin(u(3));
C13 = -sin(u(2));
C21 = sin(u(1))*sin(u(2))*cos(u(3))-cos(u(1))*sin(u(3));
C22 = sin(u(1))*sin(u(2))*sin(u(3))+cos(u(1))*cos(u(3));
C23 = sin(u(1))*cos(u(2));
C31 = cos(u(1))*sin(u(2))*cos(u(3))+sin(u(1))*sin(u(3));
C32 = cos(u(1))*sin(u(2))*sin(u(3))-sin(u(1))*cos(u(3));
C33 = cos(u(1))*cos(u(2));
    
theta = acos(0.5*(C11+C22+C33-1));

e = [C23-C32; C31-C13; C12-C21]/(2*sin(theta));
    
y = [e; theta];

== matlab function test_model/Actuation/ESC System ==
function Vb_eff   = ESC(P, Pmin, Pmax, Vb)

P1 = P(1);
P2 = P(2);
P3 = P(3);
P4 = P(4);

% Define u_Pi for each of the rotors, limiting it to be greater than 0
% u_P0 = (rotor_0_duty_cycle/100 - Pmin) / (Pmax - Pmin);
% u_P1 = (rotor_1_duty_cycle/100 - Pmin) / (Pmax - Pmin);
% u_P2 = (rotor_2_duty_cycle/100 - Pmin) / (Pmax - Pmin);
% u_P3 = (rotor_3_duty_cycle/100 - Pmin) / (Pmax - Pmin);
u_P0 = (P1 - Pmin) / (Pmax - Pmin);
u_P1 = (P2 - Pmin) / (Pmax - Pmin);
u_P2 = (P3 - Pmin) / (Pmax - Pmin);
u_P3 = (P4 - Pmin) / (Pmax - Pmin);


% Determine the effective battery voltage from each ESC
Vb_eff_0 = u_P0 * Vb;
Vb_eff_1 = u_P1 * Vb;
Vb_eff_2 = u_P2 * Vb;
Vb_eff_3 = u_P3 * Vb;
    
Vb_eff = [Vb_eff_0, Vb_eff_1, Vb_eff_2, Vb_eff_3];

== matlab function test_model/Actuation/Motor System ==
function w_dot = motor(Vb_eff, w, Rm, Kv, Kq, Kd, If, Jreq)

% Define each motors effective battery voltage
Vb_eff_0 = Vb_eff(1);
Vb_eff_1 = Vb_eff(2);
Vb_eff_2 = Vb_eff(3);
Vb_eff_3 = Vb_eff(4);

% Determine the angular velocity of each rotor from feedback
w_0 = w(1);
w_1 = w(2);
w_2 = w(3);
w_3 = w(4);

% Determine angular acceleration of each rotor
w_0_dot = 1/(Jreq*Rm*Kq) * Vb_eff_0 - 1/(Jreq*Rm*Kq*Kv) * w_0 - 1/(Jreq*Kq)*If - (Kd/Jreq) * w_0^2;
w_1_dot = 1/(Jreq*Rm*Kq) * Vb_eff_1 - 1/(Jreq*Rm*Kq*Kv) * w_1 - 1/(Jreq*Kq)*If - (Kd/Jreq) * w_1^2;
w_2_dot = 1/(Jreq*Rm*Kq) * Vb_eff_2 - 1/(Jreq*Rm*Kq*Kv) * w_2 - 1/(Jreq*Kq)*If - (Kd/Jreq) * w_2^2;
w_3_dot = 1/(Jreq*Rm*Kq) * Vb_eff_3 - 1/(Jreq*Rm*Kq*Kv) * w_3 - 1/(Jreq*Kq)*If - (Kd/Jreq) * w_3^2;

w_dot = [w_0_dot, w_1_dot, w_2_dot, w_3_dot];

== matlab function test_model/Actuation/Rotor System







 ==
function [B_omega_dot, B_vo_dot]= rotor(w_dot, w, B_Fg, B_omega, B_vo, m, Kt, Kd, rhx, rhy, rhz, Jreq, Jxx, Jyy, Jzz)

% Create J vector
J = [Jxx,  0 ,  0 ; ...
      0 , Jyy,  0 ; ...
      0 ,  0 , Jzz;];

% Create r_hi vector
rh_0 = [-rhx; rhy; -rhz];
rh_1 = [rhx; rhy; -rhz];
rh_2 = [-rhx; -rhy; -rhz];
rh_3 = [rhx; -rhy; -rhz];

% Define vector from body frame origin to center of mass
br_oc = [0; 0; 0];

% Define 3x3 Identity Matrix
I = eye(3);

% Create gamma vectors
gamma_Ti = [0; 0; -1];
gamma_omega_03 = [0; 0; 1];  %Rotors 0 and 3 use this gamma_omega vector
gamma_omega_12 = [0; 0; -1]; %Rotors 1 and 2 use this gamma_omega vector

% Define angular velocities for each rotor
w_0 = w(1);
w_1 = w(2);
w_2 = w(3);
w_3 = w(4);

% Define angular acceleration for each rotor
w_0_dot = w_dot(1);
w_1_dot = w_dot(2);
w_2_dot = w_dot(3);
w_3_dot = w_dot(4);

% Define the rotor force in the z-direction from each rotor
B_Fr_0 = Kt * w_0 * w_0 * gamma_Ti;
B_Fr_1 = Kt * w_1 * w_1 * gamma_Ti;
B_Fr_2 = Kt * w_2 * w_2 * gamma_Ti;
B_Fr_3 = Kt * w_3 * w_3 * gamma_Ti;

% Sum up the rotor forces in the z-direction from each vector to get the
% total body force in the z-direction
B_Fr = B_Fr_0 + B_Fr_1 + B_Fr_2 + B_Fr_3;

% Define the in-plane drag and induced torque produced by each rotor
 B_Q_d0 = -1 * Kd * w_0 * w_0 * gamma_omega_03;
 B_Q_d1 = -1 * Kd * w_1 * w_1 * gamma_omega_12;
 B_Q_d2 = -1 * Kd * w_2 * w_2 * gamma_omega_12;
 B_Q_d3 = -1 * Kd * w_3 * w_3 * gamma_omega_03;

% Sum up the total in-plane drag and induced torque to get the total
% in-plane drag and induced torque on the body
B_Q_d = B_Q_d0 + B_Q_d1 + B_Q_d2 + B_Q_d3;

% Define the force lever arm torque created from the force produced by each
% rotor in the z-direction
B_Q_F0 = cross( rh_0, B_Fr_0 );
B_Q_F1 = cross( rh_1, B_Fr_1 );
B_Q_F2 = cross( rh_2, B_Fr_2 );
B_Q_F3 = cross( rh_3, B_Fr_3 );

B_Q_F = B_Q_F0 + B_Q_F1 + B_Q_F2 + B_Q_F3;

%Define the change in angular momentum torque produced by each rotor 
B_Q_L0 = -1 * Jreq * ( cross(B_omega, w_0 * gamma_omega_03) + w_0_dot * gamma_omega_03 );
B_Q_L1 = -1 * Jreq * ( cross(B_omega, w_1 * gamma_omega_12) + w_1_dot * gamma_omega_12 ); 
B_Q_L2 = -1 * Jreq * ( cross(B_omega, w_2 * gamma_omega_12) + w_2_dot * gamma_omega_12 ); 
B_Q_L3 = -1 * Jreq * ( cross(B_omega, w_3 * gamma_omega_03) + w_3_dot * gamma_omega_03 );

% Sum up the total change in angular momentum torque produced by each rotor
B_Q_L = B_Q_L0 + B_Q_L1 + B_Q_L2 + B_Q_L3;

% Define the total rotor system torque as the sum of the in-plane drag and
% induced torque, force lever arm torque, and change in angular momentum
% torques
B_Q = B_Q_d + B_Q_F + B_Q_L;

% Define the body forces in the z-direction from each vector to get the
% total body force in the z-direction
B_F = B_Fr + B_Fg; 

% Define the body frame linear velocities
B_vo_dot = (m*I)^(-1) * ( B_F - cross( B_omega, m*(B_vo + cross(B_omega, br_oc)) ) );

% Define the body frame angular velocities
B_omega_dot = J ^(-1) * ( B_Q - cross(B_omega, J * B_omega) - cross(br_oc, B_F) );
